VERSION 5.8 ;
BUSBITCHARS "[]" ;
DIVIDERCHAR "/" ;
CLEARANCEMEASURE EUCLIDEAN ;

SITE coresite
    SIZE 0.0450 BY 0.1440 ;
    CLASS CORE ;
    SYMMETRY Y ;
END coresite

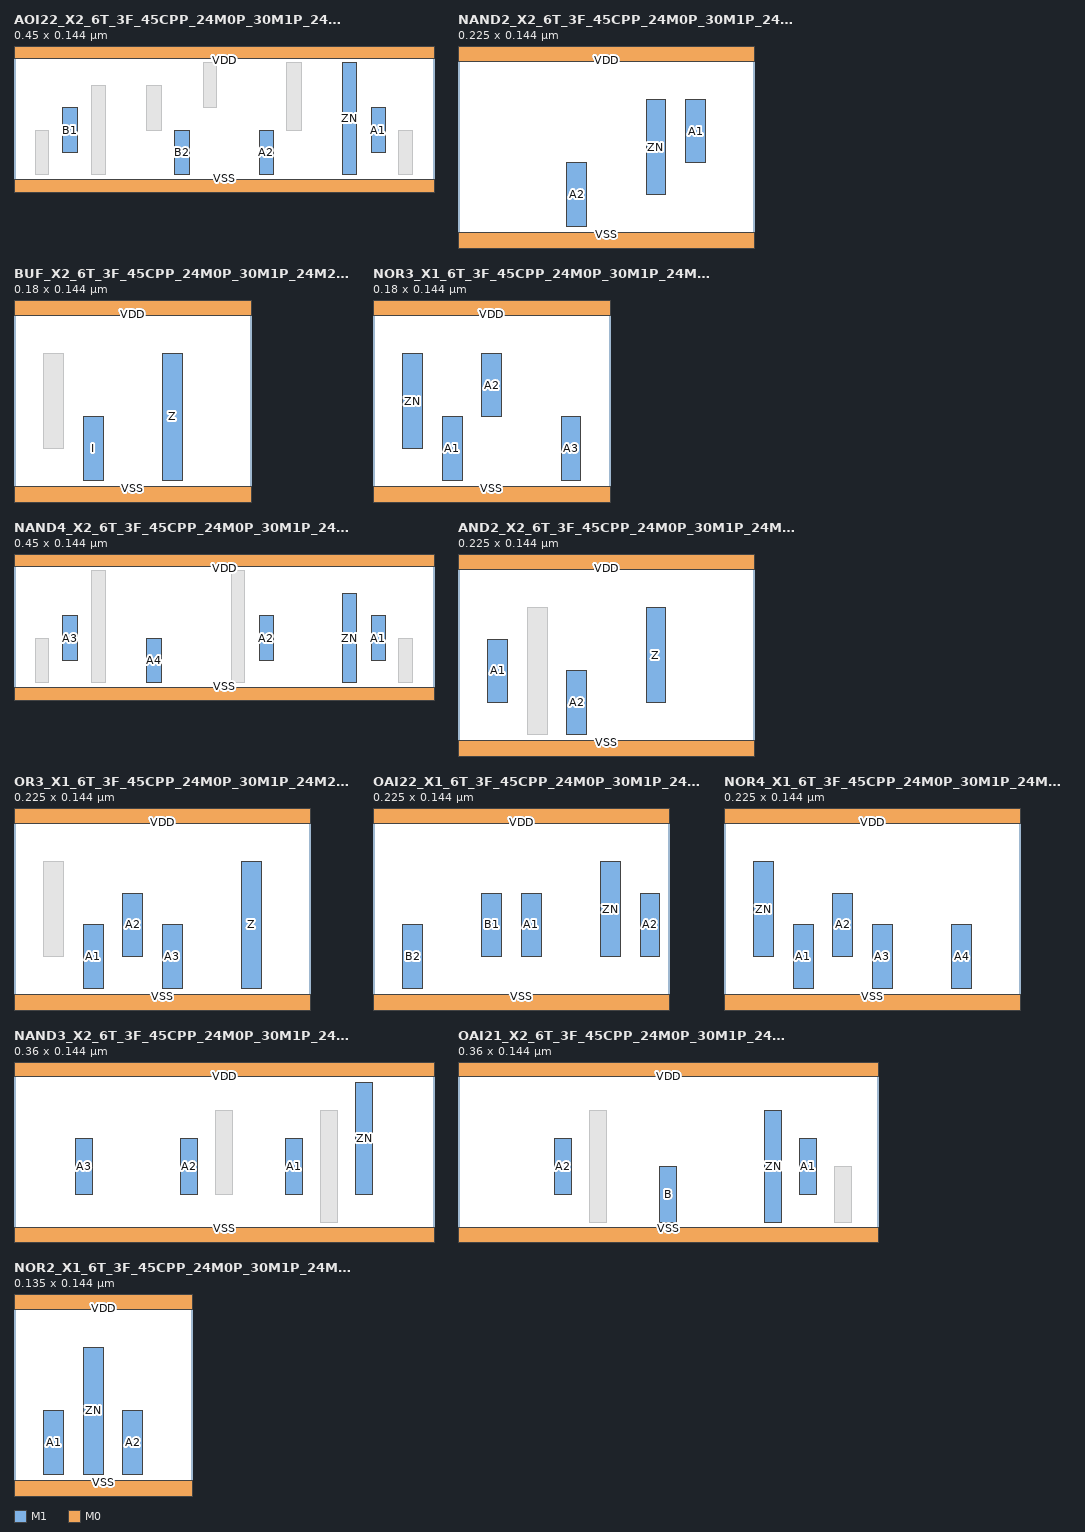
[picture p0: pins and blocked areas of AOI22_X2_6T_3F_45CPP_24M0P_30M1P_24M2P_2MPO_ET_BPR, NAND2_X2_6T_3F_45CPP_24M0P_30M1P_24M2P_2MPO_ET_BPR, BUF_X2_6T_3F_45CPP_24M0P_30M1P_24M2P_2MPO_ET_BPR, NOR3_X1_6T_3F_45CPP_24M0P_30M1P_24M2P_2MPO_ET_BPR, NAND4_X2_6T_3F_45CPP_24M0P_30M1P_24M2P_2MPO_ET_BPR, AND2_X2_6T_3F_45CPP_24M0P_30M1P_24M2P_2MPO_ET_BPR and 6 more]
MACRO AOI22_X2_6T_3F_45CPP_24M0P_30M1P_24M2P_2MPO_ET_BPR
  CLASS CORE ;
  ORIGIN 0 0 ;
  FOREIGN AOI22_X2_6T_3F_45CPP_24M0P_30M1P_24M2P_2MPO_ET_BPR 0 0 ;
  SIZE 0.4500 BY 0.1440 ;
  SYMMETRY X Y ;
  SITE coresite ;
  PIN A1
    DIRECTION INPUT ;
    USE SIGNAL ;
    PORT
      LAYER M1 ;
        RECT 0.3825 0.0840 0.3975 0.0360 ;
    END
  END A1
  PIN A2
    DIRECTION INPUT ;
    USE SIGNAL ;
    PORT
      LAYER M1 ;
        RECT 0.2625 0.0600 0.2775 0.0120 ;
    END
  END A2
  PIN ZN
    DIRECTION OUTPUT ;
    USE SIGNAL ;
    PORT
      LAYER M1 ;
        RECT 0.3525 0.1320 0.3675 0.0120 ;
    END
  END ZN
  PIN B1
    DIRECTION INPUT ;
    USE SIGNAL ;
    PORT
      LAYER M1 ;
        RECT 0.0525 0.0840 0.0675 0.0360 ;
    END
  END B1
  PIN B2
    DIRECTION INPUT ;
    USE SIGNAL ;
    PORT
      LAYER M1 ;
        RECT 0.1725 0.0600 0.1875 0.0120 ;
    END
  END B2
  PIN VDD
    DIRECTION INOUT ;
    USE POWER ;
    SHAPE ABUTMENT ;
    PORT
      LAYER M0 ;
        RECT 0.0000 0.1370 0.4500 0.1510 ;
    END
  END VDD
  PIN VSS
    DIRECTION INOUT ;
    USE GROUND ;
    SHAPE ABUTMENT ;
    PORT
      LAYER M0 ;
        RECT 0.0000 -0.0070 0.4500 0.0070 ;
    END
  END VSS
  OBS
      LAYER M1 ;
        RECT 0.0225 0.0600 0.0375 0.0120 ;
        RECT 0.2025 0.1320 0.2175 0.0840 ;
        RECT 0.4125 0.0600 0.4275 0.0120 ;
        RECT 0.1425 0.1080 0.1575 0.0600 ;
        RECT 0.0825 0.1080 0.0975 0.0120 ;
        RECT 0.2925 0.1320 0.3075 0.0600 ;
  END
END AOI22_X2_6T_3F_45CPP_24M0P_30M1P_24M2P_2MPO_ET_BPR

MACRO NAND2_X2_6T_3F_45CPP_24M0P_30M1P_24M2P_2MPO_ET_BPR
  CLASS CORE ;
  ORIGIN 0 0 ;
  FOREIGN NAND2_X2_6T_3F_45CPP_24M0P_30M1P_24M2P_2MPO_ET_BPR 0 0 ;
  SIZE 0.2250 BY 0.1440 ;
  SYMMETRY X Y ;
  SITE coresite ;
  PIN A2
    DIRECTION INPUT ;
    USE SIGNAL ;
    PORT
      LAYER M1 ;
        RECT 0.0825 0.0600 0.0975 0.0120 ;
    END
  END A2
  PIN A1
    DIRECTION INPUT ;
    USE SIGNAL ;
    PORT
      LAYER M1 ;
        RECT 0.1725 0.1080 0.1875 0.0600 ;
    END
  END A1
  PIN ZN
    DIRECTION OUTPUT ;
    USE SIGNAL ;
    PORT
      LAYER M1 ;
        RECT 0.1425 0.1080 0.1575 0.0360 ;
    END
  END ZN
  PIN VDD
    DIRECTION INOUT ;
    USE POWER ;
    SHAPE ABUTMENT ;
    PORT
      LAYER M0 ;
        RECT 0.0000 0.1370 0.2250 0.1510 ;
    END
  END VDD
  PIN VSS
    DIRECTION INOUT ;
    USE GROUND ;
    SHAPE ABUTMENT ;
    PORT
      LAYER M0 ;
        RECT 0.0000 -0.0070 0.2250 0.0070 ;
    END
  END VSS
END NAND2_X2_6T_3F_45CPP_24M0P_30M1P_24M2P_2MPO_ET_BPR

MACRO BUF_X2_6T_3F_45CPP_24M0P_30M1P_24M2P_2MPO_ET_BPR
  CLASS CORE ;
  ORIGIN 0 0 ;
  FOREIGN BUF_X2_6T_3F_45CPP_24M0P_30M1P_24M2P_2MPO_ET_BPR 0 0 ;
  SIZE 0.1800 BY 0.1440 ;
  SYMMETRY X Y ;
  SITE coresite ;
  PIN Z
    DIRECTION OUTPUT ;
    USE SIGNAL ;
    PORT
      LAYER M1 ;
        RECT 0.1125 0.1080 0.1275 0.0120 ;
    END
  END Z
  PIN I
    DIRECTION INPUT ;
    USE SIGNAL ;
    PORT
      LAYER M1 ;
        RECT 0.0525 0.0600 0.0675 0.0120 ;
    END
  END I
  PIN VDD
    DIRECTION INOUT ;
    USE POWER ;
    SHAPE ABUTMENT ;
    PORT
      LAYER M0 ;
        RECT 0.0000 0.1370 0.1800 0.1510 ;
    END
  END VDD
  PIN VSS
    DIRECTION INOUT ;
    USE GROUND ;
    SHAPE ABUTMENT ;
    PORT
      LAYER M0 ;
        RECT 0.0000 -0.0070 0.1800 0.0070 ;
    END
  END VSS
  OBS
      LAYER M1 ;
        RECT 0.0225 0.1080 0.0375 0.0360 ;
  END
END BUF_X2_6T_3F_45CPP_24M0P_30M1P_24M2P_2MPO_ET_BPR

MACRO NOR3_X1_6T_3F_45CPP_24M0P_30M1P_24M2P_2MPO_ET_BPR
  CLASS CORE ;
  ORIGIN 0 0 ;
  FOREIGN NOR3_X1_6T_3F_45CPP_24M0P_30M1P_24M2P_2MPO_ET_BPR 0 0 ;
  SIZE 0.1800 BY 0.1440 ;
  SYMMETRY X Y ;
  SITE coresite ;
  PIN A3
    DIRECTION INPUT ;
    USE SIGNAL ;
    PORT
      LAYER M1 ;
        RECT 0.1425 0.0600 0.1575 0.0120 ;
    END
  END A3
  PIN A2
    DIRECTION INPUT ;
    USE SIGNAL ;
    PORT
      LAYER M1 ;
        RECT 0.0825 0.1080 0.0975 0.0600 ;
    END
  END A2
  PIN A1
    DIRECTION INPUT ;
    USE SIGNAL ;
    PORT
      LAYER M1 ;
        RECT 0.0525 0.0600 0.0675 0.0120 ;
    END
  END A1
  PIN ZN
    DIRECTION OUTPUT ;
    USE SIGNAL ;
    PORT
      LAYER M1 ;
        RECT 0.0225 0.1080 0.0375 0.0360 ;
    END
  END ZN
  PIN VDD
    DIRECTION INOUT ;
    USE POWER ;
    SHAPE ABUTMENT ;
    PORT
      LAYER M0 ;
        RECT 0.0000 0.1370 0.1800 0.1510 ;
    END
  END VDD
  PIN VSS
    DIRECTION INOUT ;
    USE GROUND ;
    SHAPE ABUTMENT ;
    PORT
      LAYER M0 ;
        RECT 0.0000 -0.0070 0.1800 0.0070 ;
    END
  END VSS
END NOR3_X1_6T_3F_45CPP_24M0P_30M1P_24M2P_2MPO_ET_BPR

MACRO NAND4_X2_6T_3F_45CPP_24M0P_30M1P_24M2P_2MPO_ET_BPR
  CLASS CORE ;
  ORIGIN 0 0 ;
  FOREIGN NAND4_X2_6T_3F_45CPP_24M0P_30M1P_24M2P_2MPO_ET_BPR 0 0 ;
  SIZE 0.4500 BY 0.1440 ;
  SYMMETRY X Y ;
  SITE coresite ;
  PIN ZN
    DIRECTION OUTPUT ;
    USE SIGNAL ;
    PORT
      LAYER M1 ;
        RECT 0.3525 0.1080 0.3675 0.0120 ;
    END
  END ZN
  PIN A1
    DIRECTION INPUT ;
    USE SIGNAL ;
    PORT
      LAYER M1 ;
        RECT 0.3825 0.0840 0.3975 0.0360 ;
    END
  END A1
  PIN A2
    DIRECTION INPUT ;
    USE SIGNAL ;
    PORT
      LAYER M1 ;
        RECT 0.2625 0.0840 0.2775 0.0360 ;
    END
  END A2
  PIN A3
    DIRECTION INPUT ;
    USE SIGNAL ;
    PORT
      LAYER M1 ;
        RECT 0.0525 0.0840 0.0675 0.0360 ;
    END
  END A3
  PIN A4
    DIRECTION INPUT ;
    USE SIGNAL ;
    PORT
      LAYER M1 ;
        RECT 0.1425 0.0600 0.1575 0.0120 ;
    END
  END A4
  PIN VDD
    DIRECTION INOUT ;
    USE POWER ;
    SHAPE ABUTMENT ;
    PORT
      LAYER M0 ;
        RECT 0.0000 0.1370 0.4500 0.1510 ;
    END
  END VDD
  PIN VSS
    DIRECTION INOUT ;
    USE GROUND ;
    SHAPE ABUTMENT ;
    PORT
      LAYER M0 ;
        RECT 0.0000 -0.0070 0.4500 0.0070 ;
    END
  END VSS
  OBS
      LAYER M1 ;
        RECT 0.0825 0.1320 0.0975 0.0120 ;
        RECT 0.2325 0.1320 0.2475 0.0120 ;
        RECT 0.0225 0.0600 0.0375 0.0120 ;
        RECT 0.4125 0.0600 0.4275 0.0120 ;
  END
END NAND4_X2_6T_3F_45CPP_24M0P_30M1P_24M2P_2MPO_ET_BPR

MACRO AND2_X2_6T_3F_45CPP_24M0P_30M1P_24M2P_2MPO_ET_BPR
  CLASS CORE ;
  ORIGIN 0 0 ;
  FOREIGN AND2_X2_6T_3F_45CPP_24M0P_30M1P_24M2P_2MPO_ET_BPR 0 0 ;
  SIZE 0.2250 BY 0.1440 ;
  SYMMETRY X Y ;
  SITE coresite ;
  PIN Z
    DIRECTION OUTPUT ;
    USE SIGNAL ;
    PORT
      LAYER M1 ;
        RECT 0.1425 0.1080 0.1575 0.0360 ;
    END
  END Z
  PIN A1
    DIRECTION INPUT ;
    USE SIGNAL ;
    PORT
      LAYER M1 ;
        RECT 0.0225 0.0840 0.0375 0.0360 ;
    END
  END A1
  PIN A2
    DIRECTION INPUT ;
    USE SIGNAL ;
    PORT
      LAYER M1 ;
        RECT 0.0825 0.0600 0.0975 0.0120 ;
    END
  END A2
  PIN VDD
    DIRECTION INOUT ;
    USE POWER ;
    SHAPE ABUTMENT ;
    PORT
      LAYER M0 ;
        RECT 0.0000 0.1370 0.2250 0.1510 ;
    END
  END VDD
  PIN VSS
    DIRECTION INOUT ;
    USE GROUND ;
    SHAPE ABUTMENT ;
    PORT
      LAYER M0 ;
        RECT 0.0000 -0.0070 0.2250 0.0070 ;
    END
  END VSS
  OBS
      LAYER M1 ;
        RECT 0.0525 0.1080 0.0675 0.0120 ;
  END
END AND2_X2_6T_3F_45CPP_24M0P_30M1P_24M2P_2MPO_ET_BPR

MACRO OR3_X1_6T_3F_45CPP_24M0P_30M1P_24M2P_2MPO_ET_BPR
  CLASS CORE ;
  ORIGIN 0 0 ;
  FOREIGN OR3_X1_6T_3F_45CPP_24M0P_30M1P_24M2P_2MPO_ET_BPR 0 0 ;
  SIZE 0.2250 BY 0.1440 ;
  SYMMETRY X Y ;
  SITE coresite ;
  PIN Z
    DIRECTION OUTPUT ;
    USE SIGNAL ;
    PORT
      LAYER M1 ;
        RECT 0.1725 0.1080 0.1875 0.0120 ;
    END
  END Z
  PIN A1
    DIRECTION INPUT ;
    USE SIGNAL ;
    PORT
      LAYER M1 ;
        RECT 0.0525 0.0600 0.0675 0.0120 ;
    END
  END A1
  PIN A2
    DIRECTION INPUT ;
    USE SIGNAL ;
    PORT
      LAYER M1 ;
        RECT 0.0825 0.0840 0.0975 0.0360 ;
    END
  END A2
  PIN A3
    DIRECTION INPUT ;
    USE SIGNAL ;
    PORT
      LAYER M1 ;
        RECT 0.1125 0.0600 0.1275 0.0120 ;
    END
  END A3
  PIN VDD
    DIRECTION INOUT ;
    USE POWER ;
    SHAPE ABUTMENT ;
    PORT
      LAYER M0 ;
        RECT 0.0000 0.1370 0.2250 0.1510 ;
    END
  END VDD
  PIN VSS
    DIRECTION INOUT ;
    USE GROUND ;
    SHAPE ABUTMENT ;
    PORT
      LAYER M0 ;
        RECT 0.0000 -0.0070 0.2250 0.0070 ;
    END
  END VSS
  OBS
      LAYER M1 ;
        RECT 0.0225 0.1080 0.0375 0.0360 ;
  END
END OR3_X1_6T_3F_45CPP_24M0P_30M1P_24M2P_2MPO_ET_BPR

MACRO OAI22_X1_6T_3F_45CPP_24M0P_30M1P_24M2P_2MPO_ET_BPR
  CLASS CORE ;
  ORIGIN 0 0 ;
  FOREIGN OAI22_X1_6T_3F_45CPP_24M0P_30M1P_24M2P_2MPO_ET_BPR 0 0 ;
  SIZE 0.2250 BY 0.1440 ;
  SYMMETRY X Y ;
  SITE coresite ;
  PIN A2
    DIRECTION INPUT ;
    USE SIGNAL ;
    PORT
      LAYER M1 ;
        RECT 0.2025 0.0840 0.2175 0.0360 ;
    END
  END A2
  PIN ZN
    DIRECTION OUTPUT ;
    USE SIGNAL ;
    PORT
      LAYER M1 ;
        RECT 0.1725 0.1080 0.1875 0.0360 ;
    END
  END ZN
  PIN A1
    DIRECTION INPUT ;
    USE SIGNAL ;
    PORT
      LAYER M1 ;
        RECT 0.1125 0.0840 0.1275 0.0360 ;
    END
  END A1
  PIN B1
    DIRECTION INPUT ;
    USE SIGNAL ;
    PORT
      LAYER M1 ;
        RECT 0.0825 0.0840 0.0975 0.0360 ;
    END
  END B1
  PIN B2
    DIRECTION INPUT ;
    USE SIGNAL ;
    PORT
      LAYER M1 ;
        RECT 0.0225 0.0600 0.0375 0.0120 ;
    END
  END B2
  PIN VDD
    DIRECTION INOUT ;
    USE POWER ;
    SHAPE ABUTMENT ;
    PORT
      LAYER M0 ;
        RECT 0.0000 0.1370 0.2250 0.1510 ;
    END
  END VDD
  PIN VSS
    DIRECTION INOUT ;
    USE GROUND ;
    SHAPE ABUTMENT ;
    PORT
      LAYER M0 ;
        RECT 0.0000 -0.0070 0.2250 0.0070 ;
    END
  END VSS
END OAI22_X1_6T_3F_45CPP_24M0P_30M1P_24M2P_2MPO_ET_BPR

MACRO NOR4_X1_6T_3F_45CPP_24M0P_30M1P_24M2P_2MPO_ET_BPR
  CLASS CORE ;
  ORIGIN 0 0 ;
  FOREIGN NOR4_X1_6T_3F_45CPP_24M0P_30M1P_24M2P_2MPO_ET_BPR 0 0 ;
  SIZE 0.2250 BY 0.1440 ;
  SYMMETRY X Y ;
  SITE coresite ;
  PIN A4
    DIRECTION INPUT ;
    USE SIGNAL ;
    PORT
      LAYER M1 ;
        RECT 0.1725 0.0600 0.1875 0.0120 ;
    END
  END A4
  PIN A3
    DIRECTION INPUT ;
    USE SIGNAL ;
    PORT
      LAYER M1 ;
        RECT 0.1125 0.0600 0.1275 0.0120 ;
    END
  END A3
  PIN A2
    DIRECTION INPUT ;
    USE SIGNAL ;
    PORT
      LAYER M1 ;
        RECT 0.0825 0.0840 0.0975 0.0360 ;
    END
  END A2
  PIN A1
    DIRECTION INPUT ;
    USE SIGNAL ;
    PORT
      LAYER M1 ;
        RECT 0.0525 0.0600 0.0675 0.0120 ;
    END
  END A1
  PIN ZN
    DIRECTION OUTPUT ;
    USE SIGNAL ;
    PORT
      LAYER M1 ;
        RECT 0.0225 0.1080 0.0375 0.0360 ;
    END
  END ZN
  PIN VDD
    DIRECTION INOUT ;
    USE POWER ;
    SHAPE ABUTMENT ;
    PORT
      LAYER M0 ;
        RECT 0.0000 0.1370 0.2250 0.1510 ;
    END
  END VDD
  PIN VSS
    DIRECTION INOUT ;
    USE GROUND ;
    SHAPE ABUTMENT ;
    PORT
      LAYER M0 ;
        RECT 0.0000 -0.0070 0.2250 0.0070 ;
    END
  END VSS
END NOR4_X1_6T_3F_45CPP_24M0P_30M1P_24M2P_2MPO_ET_BPR

MACRO NAND3_X2_6T_3F_45CPP_24M0P_30M1P_24M2P_2MPO_ET_BPR
  CLASS CORE ;
  ORIGIN 0 0 ;
  FOREIGN NAND3_X2_6T_3F_45CPP_24M0P_30M1P_24M2P_2MPO_ET_BPR 0 0 ;
  SIZE 0.3600 BY 0.1440 ;
  SYMMETRY X Y ;
  SITE coresite ;
  PIN A1
    DIRECTION INPUT ;
    USE SIGNAL ;
    PORT
      LAYER M1 ;
        RECT 0.2325 0.0840 0.2475 0.0360 ;
    END
  END A1
  PIN ZN
    DIRECTION OUTPUT ;
    USE SIGNAL ;
    PORT
      LAYER M1 ;
        RECT 0.2925 0.1320 0.3075 0.0360 ;
    END
  END ZN
  PIN A2
    DIRECTION INPUT ;
    USE SIGNAL ;
    PORT
      LAYER M1 ;
        RECT 0.1425 0.0840 0.1575 0.0360 ;
    END
  END A2
  PIN A3
    DIRECTION INPUT ;
    USE SIGNAL ;
    PORT
      LAYER M1 ;
        RECT 0.0525 0.0840 0.0675 0.0360 ;
    END
  END A3
  PIN VDD
    DIRECTION INOUT ;
    USE POWER ;
    SHAPE ABUTMENT ;
    PORT
      LAYER M0 ;
        RECT 0.0000 0.1370 0.3600 0.1510 ;
    END
  END VDD
  PIN VSS
    DIRECTION INOUT ;
    USE GROUND ;
    SHAPE ABUTMENT ;
    PORT
      LAYER M0 ;
        RECT 0.0000 -0.0070 0.3600 0.0070 ;
    END
  END VSS
  OBS
      LAYER M1 ;
        RECT 0.2625 0.1080 0.2775 0.0120 ;
        RECT 0.1725 0.1080 0.1875 0.0360 ;
  END
END NAND3_X2_6T_3F_45CPP_24M0P_30M1P_24M2P_2MPO_ET_BPR

MACRO OAI21_X2_6T_3F_45CPP_24M0P_30M1P_24M2P_2MPO_ET_BPR
  CLASS CORE ;
  ORIGIN 0 0 ;
  FOREIGN OAI21_X2_6T_3F_45CPP_24M0P_30M1P_24M2P_2MPO_ET_BPR 0 0 ;
  SIZE 0.3600 BY 0.1440 ;
  SYMMETRY X Y ;
  SITE coresite ;
  PIN A2
    DIRECTION INPUT ;
    USE SIGNAL ;
    PORT
      LAYER M1 ;
        RECT 0.0825 0.0840 0.0975 0.0360 ;
    END
  END A2
  PIN A1
    DIRECTION INPUT ;
    USE SIGNAL ;
    PORT
      LAYER M1 ;
        RECT 0.2925 0.0840 0.3075 0.0360 ;
    END
  END A1
  PIN ZN
    DIRECTION OUTPUT ;
    USE SIGNAL ;
    PORT
      LAYER M1 ;
        RECT 0.2625 0.1080 0.2775 0.0120 ;
    END
  END ZN
  PIN B
    DIRECTION INPUT ;
    USE SIGNAL ;
    PORT
      LAYER M1 ;
        RECT 0.1725 0.0600 0.1875 0.0120 ;
    END
  END B
  PIN VDD
    DIRECTION INOUT ;
    USE POWER ;
    SHAPE ABUTMENT ;
    PORT
      LAYER M0 ;
        RECT 0.0000 0.1370 0.3600 0.1510 ;
    END
  END VDD
  PIN VSS
    DIRECTION INOUT ;
    USE GROUND ;
    SHAPE ABUTMENT ;
    PORT
      LAYER M0 ;
        RECT 0.0000 -0.0070 0.3600 0.0070 ;
    END
  END VSS
  OBS
      LAYER M1 ;
        RECT 0.3225 0.0600 0.3375 0.0120 ;
        RECT 0.1125 0.1080 0.1275 0.0120 ;
  END
END OAI21_X2_6T_3F_45CPP_24M0P_30M1P_24M2P_2MPO_ET_BPR

MACRO NOR2_X1_6T_3F_45CPP_24M0P_30M1P_24M2P_2MPO_ET_BPR
  CLASS CORE ;
  ORIGIN 0 0 ;
  FOREIGN NOR2_X1_6T_3F_45CPP_24M0P_30M1P_24M2P_2MPO_ET_BPR 0 0 ;
  SIZE 0.1350 BY 0.1440 ;
  SYMMETRY X Y ;
  SITE coresite ;
  PIN A2
    DIRECTION INPUT ;
    USE SIGNAL ;
    PORT
      LAYER M1 ;
        RECT 0.0825 0.0600 0.0975 0.0120 ;
    END
  END A2
  PIN A1
    DIRECTION INPUT ;
    USE SIGNAL ;
    PORT
      LAYER M1 ;
        RECT 0.0225 0.0600 0.0375 0.0120 ;
    END
  END A1
  PIN ZN
    DIRECTION OUTPUT ;
    USE SIGNAL ;
    PORT
      LAYER M1 ;
        RECT 0.0525 0.1080 0.0675 0.0120 ;
    END
  END ZN
  PIN VDD
    DIRECTION INOUT ;
    USE POWER ;
    SHAPE ABUTMENT ;
    PORT
      LAYER M0 ;
        RECT 0.0000 0.1370 0.1350 0.1510 ;
    END
  END VDD
  PIN VSS
    DIRECTION INOUT ;
    USE GROUND ;
    SHAPE ABUTMENT ;
    PORT
      LAYER M0 ;
        RECT 0.0000 -0.0070 0.1350 0.0070 ;
    END
  END VSS
END NOR2_X1_6T_3F_45CPP_24M0P_30M1P_24M2P_2MPO_ET_BPR

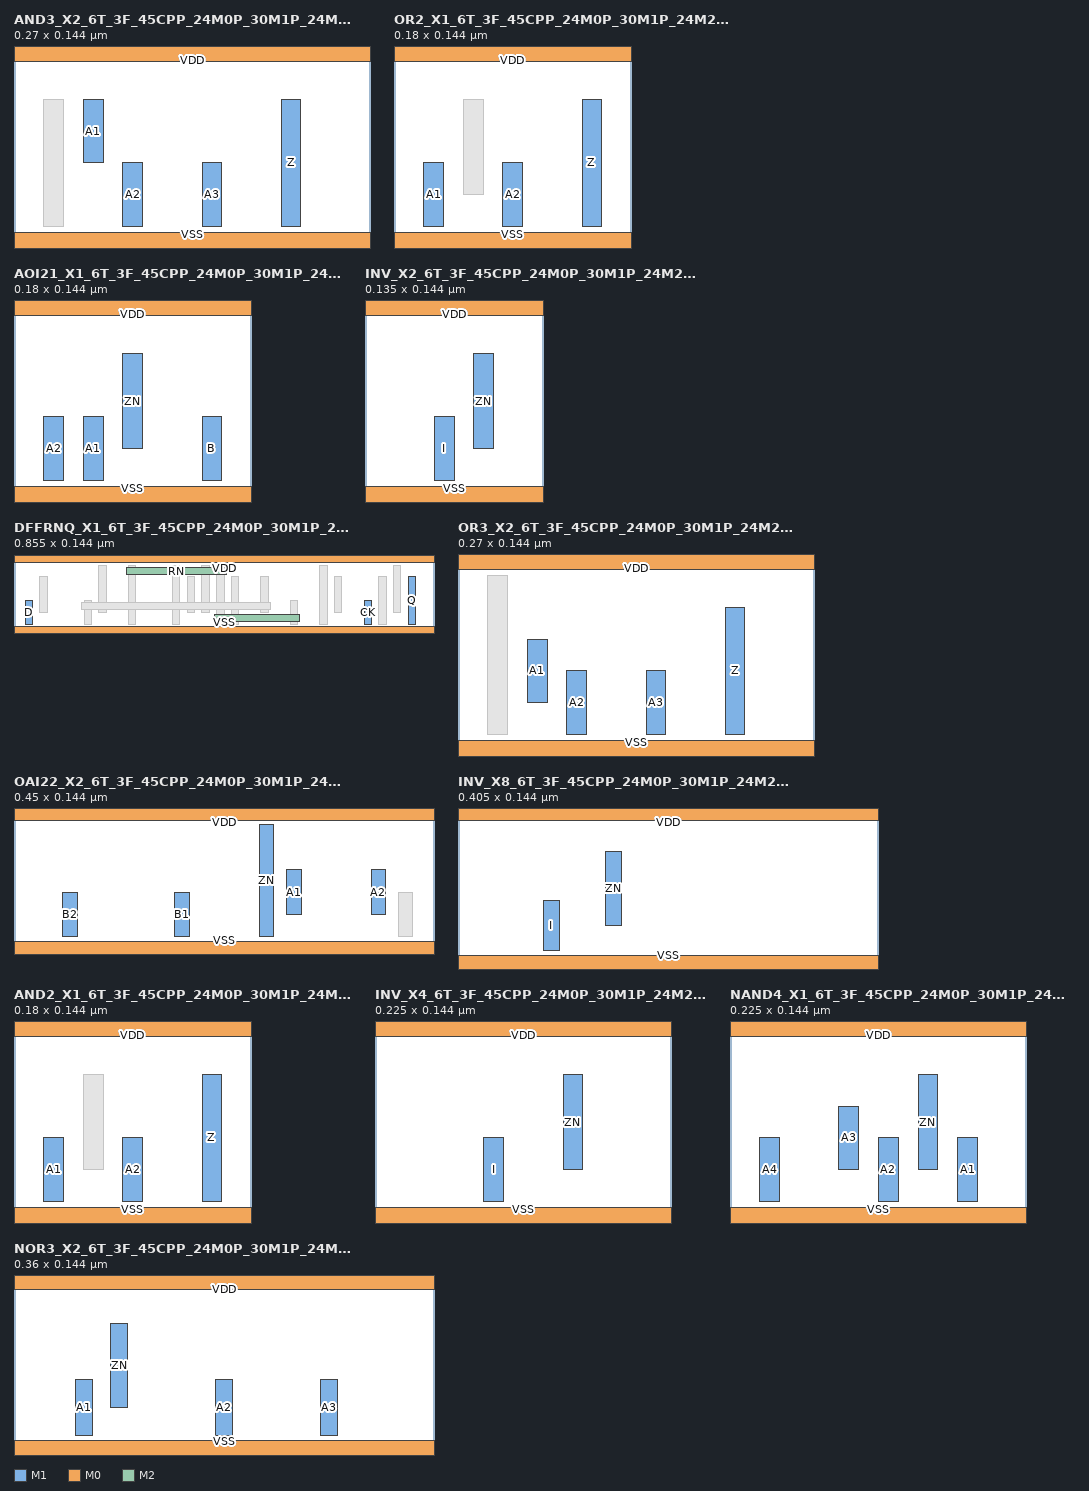
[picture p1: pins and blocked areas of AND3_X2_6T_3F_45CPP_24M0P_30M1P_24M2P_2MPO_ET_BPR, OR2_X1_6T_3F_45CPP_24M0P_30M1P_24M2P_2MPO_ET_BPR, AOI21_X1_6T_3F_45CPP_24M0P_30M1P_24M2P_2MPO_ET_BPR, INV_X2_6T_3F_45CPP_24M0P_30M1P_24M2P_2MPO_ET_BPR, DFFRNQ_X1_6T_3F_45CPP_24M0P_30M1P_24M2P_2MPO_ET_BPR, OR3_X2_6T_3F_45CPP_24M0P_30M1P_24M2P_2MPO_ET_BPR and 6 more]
MACRO AND3_X2_6T_3F_45CPP_24M0P_30M1P_24M2P_2MPO_ET_BPR
  CLASS CORE ;
  ORIGIN 0 0 ;
  FOREIGN AND3_X2_6T_3F_45CPP_24M0P_30M1P_24M2P_2MPO_ET_BPR 0 0 ;
  SIZE 0.2700 BY 0.1440 ;
  SYMMETRY X Y ;
  SITE coresite ;
  PIN Z
    DIRECTION OUTPUT ;
    USE SIGNAL ;
    PORT
      LAYER M1 ;
        RECT 0.2025 0.1080 0.2175 0.0120 ;
    END
  END Z
  PIN A3
    DIRECTION INPUT ;
    USE SIGNAL ;
    PORT
      LAYER M1 ;
        RECT 0.1425 0.0600 0.1575 0.0120 ;
    END
  END A3
  PIN A1
    DIRECTION INPUT ;
    USE SIGNAL ;
    PORT
      LAYER M1 ;
        RECT 0.0525 0.1080 0.0675 0.0600 ;
    END
  END A1
  PIN A2
    DIRECTION INPUT ;
    USE SIGNAL ;
    PORT
      LAYER M1 ;
        RECT 0.0825 0.0600 0.0975 0.0120 ;
    END
  END A2
  PIN VDD
    DIRECTION INOUT ;
    USE POWER ;
    SHAPE ABUTMENT ;
    PORT
      LAYER M0 ;
        RECT 0.0000 0.1370 0.2700 0.1510 ;
    END
  END VDD
  PIN VSS
    DIRECTION INOUT ;
    USE GROUND ;
    SHAPE ABUTMENT ;
    PORT
      LAYER M0 ;
        RECT 0.0000 -0.0070 0.2700 0.0070 ;
    END
  END VSS
  OBS
      LAYER M1 ;
        RECT 0.0225 0.1080 0.0375 0.0120 ;
  END
END AND3_X2_6T_3F_45CPP_24M0P_30M1P_24M2P_2MPO_ET_BPR

MACRO OR2_X1_6T_3F_45CPP_24M0P_30M1P_24M2P_2MPO_ET_BPR
  CLASS CORE ;
  ORIGIN 0 0 ;
  FOREIGN OR2_X1_6T_3F_45CPP_24M0P_30M1P_24M2P_2MPO_ET_BPR 0 0 ;
  SIZE 0.1800 BY 0.1440 ;
  SYMMETRY X Y ;
  SITE coresite ;
  PIN Z
    DIRECTION OUTPUT ;
    USE SIGNAL ;
    PORT
      LAYER M1 ;
        RECT 0.1425 0.1080 0.1575 0.0120 ;
    END
  END Z
  PIN A1
    DIRECTION INPUT ;
    USE SIGNAL ;
    PORT
      LAYER M1 ;
        RECT 0.0225 0.0600 0.0375 0.0120 ;
    END
  END A1
  PIN A2
    DIRECTION INPUT ;
    USE SIGNAL ;
    PORT
      LAYER M1 ;
        RECT 0.0825 0.0600 0.0975 0.0120 ;
    END
  END A2
  PIN VDD
    DIRECTION INOUT ;
    USE POWER ;
    SHAPE ABUTMENT ;
    PORT
      LAYER M0 ;
        RECT 0.0000 0.1370 0.1800 0.1510 ;
    END
  END VDD
  PIN VSS
    DIRECTION INOUT ;
    USE GROUND ;
    SHAPE ABUTMENT ;
    PORT
      LAYER M0 ;
        RECT 0.0000 -0.0070 0.1800 0.0070 ;
    END
  END VSS
  OBS
      LAYER M1 ;
        RECT 0.0525 0.1080 0.0675 0.0360 ;
  END
END OR2_X1_6T_3F_45CPP_24M0P_30M1P_24M2P_2MPO_ET_BPR

MACRO AOI21_X1_6T_3F_45CPP_24M0P_30M1P_24M2P_2MPO_ET_BPR
  CLASS CORE ;
  ORIGIN 0 0 ;
  FOREIGN AOI21_X1_6T_3F_45CPP_24M0P_30M1P_24M2P_2MPO_ET_BPR 0 0 ;
  SIZE 0.1800 BY 0.1440 ;
  SYMMETRY X Y ;
  SITE coresite ;
  PIN B
    DIRECTION INPUT ;
    USE SIGNAL ;
    PORT
      LAYER M1 ;
        RECT 0.1425 0.0600 0.1575 0.0120 ;
    END
  END B
  PIN ZN
    DIRECTION OUTPUT ;
    USE SIGNAL ;
    PORT
      LAYER M1 ;
        RECT 0.0825 0.1080 0.0975 0.0360 ;
    END
  END ZN
  PIN A1
    DIRECTION INPUT ;
    USE SIGNAL ;
    PORT
      LAYER M1 ;
        RECT 0.0525 0.0600 0.0675 0.0120 ;
    END
  END A1
  PIN A2
    DIRECTION INPUT ;
    USE SIGNAL ;
    PORT
      LAYER M1 ;
        RECT 0.0225 0.0600 0.0375 0.0120 ;
    END
  END A2
  PIN VDD
    DIRECTION INOUT ;
    USE POWER ;
    SHAPE ABUTMENT ;
    PORT
      LAYER M0 ;
        RECT 0.0000 0.1370 0.1800 0.1510 ;
    END
  END VDD
  PIN VSS
    DIRECTION INOUT ;
    USE GROUND ;
    SHAPE ABUTMENT ;
    PORT
      LAYER M0 ;
        RECT 0.0000 -0.0070 0.1800 0.0070 ;
    END
  END VSS
END AOI21_X1_6T_3F_45CPP_24M0P_30M1P_24M2P_2MPO_ET_BPR

MACRO INV_X2_6T_3F_45CPP_24M0P_30M1P_24M2P_2MPO_ET_BPR
  CLASS CORE ;
  ORIGIN 0 0 ;
  FOREIGN INV_X2_6T_3F_45CPP_24M0P_30M1P_24M2P_2MPO_ET_BPR 0 0 ;
  SIZE 0.1350 BY 0.1440 ;
  SYMMETRY X Y ;
  SITE coresite ;
  PIN ZN
    DIRECTION OUTPUT ;
    USE SIGNAL ;
    PORT
      LAYER M1 ;
        RECT 0.0825 0.1080 0.0975 0.0360 ;
    END
  END ZN
  PIN I
    DIRECTION INPUT ;
    USE SIGNAL ;
    PORT
      LAYER M1 ;
        RECT 0.0525 0.0600 0.0675 0.0120 ;
    END
  END I
  PIN VDD
    DIRECTION INOUT ;
    USE POWER ;
    SHAPE ABUTMENT ;
    PORT
      LAYER M0 ;
        RECT 0.0000 0.1370 0.1350 0.1510 ;
    END
  END VDD
  PIN VSS
    DIRECTION INOUT ;
    USE GROUND ;
    SHAPE ABUTMENT ;
    PORT
      LAYER M0 ;
        RECT 0.0000 -0.0070 0.1350 0.0070 ;
    END
  END VSS
END INV_X2_6T_3F_45CPP_24M0P_30M1P_24M2P_2MPO_ET_BPR

MACRO DFFRNQ_X1_6T_3F_45CPP_24M0P_30M1P_24M2P_2MPO_ET_BPR
  CLASS CORE ;
  ORIGIN 0 0 ;
  FOREIGN DFFRNQ_X1_6T_3F_45CPP_24M0P_30M1P_24M2P_2MPO_ET_BPR 0 0 ;
  SIZE 0.8550 BY 0.1440 ;
  SYMMETRY X Y ;
  SITE coresite ;
  PIN Q
    DIRECTION OUTPUT ;
    USE SIGNAL ;
    PORT
      LAYER M1 ;
        RECT 0.8025 0.1080 0.8175 0.0120 ;
    END
  END Q
  PIN RN
    DIRECTION INPUT ;
    USE SIGNAL ;
    PORT
      LAYER M2 ;
        RECT 0.4080 0.0170 0.5820 0.0310 ;
        RECT 0.2280 0.1130 0.4320 0.1270 ;
    END
  END RN
  PIN D
    DIRECTION INPUT ;
    USE SIGNAL ;
    PORT
      LAYER M1 ;
        RECT 0.0225 0.0600 0.0375 0.0120 ;
    END
  END D
  PIN CK
    DIRECTION INPUT ;
    USE SIGNAL ;
    PORT
      LAYER M1 ;
        RECT 0.7125 0.0600 0.7275 0.0120 ;
    END
  END CK
  PIN VDD
    DIRECTION INOUT ;
    USE POWER ;
    SHAPE ABUTMENT ;
    PORT
      LAYER M0 ;
        RECT 0.0000 0.1370 0.8550 0.1510 ;
    END
  END VDD
  PIN VSS
    DIRECTION INOUT ;
    USE GROUND ;
    SHAPE ABUTMENT ;
    PORT
      LAYER M0 ;
        RECT 0.0000 -0.0070 0.8550 0.0070 ;
    END
  END VSS
  OBS
      LAYER V1 ;
        RECT 0.5030 0.0410 0.5170 0.0550 ;
        RECT 0.3830 0.0410 0.3970 0.0550 ;
        RECT 0.1430 0.0410 0.1570 0.0550 ;
        RECT 0.5630 0.0170 0.5770 0.0310 ;
        RECT 0.4130 0.0170 0.4270 0.0310 ;
        RECT 0.4130 0.1130 0.4270 0.1270 ;
        RECT 0.2330 0.1130 0.2470 0.1270 ;
      LAYER M1 ;
        RECT 0.4425 0.1080 0.4575 0.0120 ;
        RECT 0.6225 0.1320 0.6375 0.0120 ;
        RECT 0.1725 0.1320 0.1875 0.0360 ;
        RECT 0.3825 0.1320 0.3975 0.0360 ;
        RECT 0.7425 0.1080 0.7575 0.0120 ;
        RECT 0.5025 0.1080 0.5175 0.0360 ;
        RECT 0.3525 0.1080 0.3675 0.0360 ;
        RECT 0.6525 0.1080 0.6675 0.0360 ;
        RECT 0.0525 0.1080 0.0675 0.0360 ;
        RECT 0.3225 0.1320 0.3375 0.0120 ;
        RECT 0.7725 0.1320 0.7875 0.0360 ;
        RECT 0.1425 0.0600 0.1575 0.0120 ;
        RECT 0.4125 0.1320 0.4275 0.0120 ;
        RECT 0.2325 0.1320 0.2475 0.0120 ;
        RECT 0.5625 0.0600 0.5775 0.0120 ;
      LAYER M2 ;
        RECT 0.1380 0.0410 0.5220 0.0550 ;
  END
END DFFRNQ_X1_6T_3F_45CPP_24M0P_30M1P_24M2P_2MPO_ET_BPR

MACRO OR3_X2_6T_3F_45CPP_24M0P_30M1P_24M2P_2MPO_ET_BPR
  CLASS CORE ;
  ORIGIN 0 0 ;
  FOREIGN OR3_X2_6T_3F_45CPP_24M0P_30M1P_24M2P_2MPO_ET_BPR 0 0 ;
  SIZE 0.2700 BY 0.1440 ;
  SYMMETRY X Y ;
  SITE coresite ;
  PIN Z
    DIRECTION OUTPUT ;
    USE SIGNAL ;
    PORT
      LAYER M1 ;
        RECT 0.2025 0.1080 0.2175 0.0120 ;
    END
  END Z
  PIN A3
    DIRECTION INPUT ;
    USE SIGNAL ;
    PORT
      LAYER M1 ;
        RECT 0.1425 0.0600 0.1575 0.0120 ;
    END
  END A3
  PIN A1
    DIRECTION INPUT ;
    USE SIGNAL ;
    PORT
      LAYER M1 ;
        RECT 0.0525 0.0840 0.0675 0.0360 ;
    END
  END A1
  PIN A2
    DIRECTION INPUT ;
    USE SIGNAL ;
    PORT
      LAYER M1 ;
        RECT 0.0825 0.0600 0.0975 0.0120 ;
    END
  END A2
  PIN VDD
    DIRECTION INOUT ;
    USE POWER ;
    SHAPE ABUTMENT ;
    PORT
      LAYER M0 ;
        RECT 0.0000 0.1370 0.2700 0.1510 ;
    END
  END VDD
  PIN VSS
    DIRECTION INOUT ;
    USE GROUND ;
    SHAPE ABUTMENT ;
    PORT
      LAYER M0 ;
        RECT 0.0000 -0.0070 0.2700 0.0070 ;
    END
  END VSS
  OBS
      LAYER M1 ;
        RECT 0.0225 0.1320 0.0375 0.0120 ;
  END
END OR3_X2_6T_3F_45CPP_24M0P_30M1P_24M2P_2MPO_ET_BPR

MACRO OAI22_X2_6T_3F_45CPP_24M0P_30M1P_24M2P_2MPO_ET_BPR
  CLASS CORE ;
  ORIGIN 0 0 ;
  FOREIGN OAI22_X2_6T_3F_45CPP_24M0P_30M1P_24M2P_2MPO_ET_BPR 0 0 ;
  SIZE 0.4500 BY 0.1440 ;
  SYMMETRY X Y ;
  SITE coresite ;
  PIN A1
    DIRECTION INPUT ;
    USE SIGNAL ;
    PORT
      LAYER M1 ;
        RECT 0.2925 0.0840 0.3075 0.0360 ;
    END
  END A1
  PIN ZN
    DIRECTION OUTPUT ;
    USE SIGNAL ;
    PORT
      LAYER M1 ;
        RECT 0.2625 0.1320 0.2775 0.0120 ;
    END
  END ZN
  PIN A2
    DIRECTION INPUT ;
    USE SIGNAL ;
    PORT
      LAYER M1 ;
        RECT 0.3825 0.0840 0.3975 0.0360 ;
    END
  END A2
  PIN B1
    DIRECTION INPUT ;
    USE SIGNAL ;
    PORT
      LAYER M1 ;
        RECT 0.1725 0.0600 0.1875 0.0120 ;
    END
  END B1
  PIN B2
    DIRECTION INPUT ;
    USE SIGNAL ;
    PORT
      LAYER M1 ;
        RECT 0.0525 0.0600 0.0675 0.0120 ;
    END
  END B2
  PIN VDD
    DIRECTION INOUT ;
    USE POWER ;
    SHAPE ABUTMENT ;
    PORT
      LAYER M0 ;
        RECT 0.0000 0.1370 0.4500 0.1510 ;
    END
  END VDD
  PIN VSS
    DIRECTION INOUT ;
    USE GROUND ;
    SHAPE ABUTMENT ;
    PORT
      LAYER M0 ;
        RECT 0.0000 -0.0070 0.4500 0.0070 ;
    END
  END VSS
  OBS
      LAYER M1 ;
        RECT 0.4125 0.0600 0.4275 0.0120 ;
  END
END OAI22_X2_6T_3F_45CPP_24M0P_30M1P_24M2P_2MPO_ET_BPR

MACRO INV_X8_6T_3F_45CPP_24M0P_30M1P_24M2P_2MPO_ET_BPR
  CLASS CORE ;
  ORIGIN 0 0 ;
  FOREIGN INV_X8_6T_3F_45CPP_24M0P_30M1P_24M2P_2MPO_ET_BPR 0 0 ;
  SIZE 0.4050 BY 0.1440 ;
  SYMMETRY X Y ;
  SITE coresite ;
  PIN ZN
    DIRECTION OUTPUT ;
    USE SIGNAL ;
    PORT
      LAYER M1 ;
        RECT 0.1425 0.1080 0.1575 0.0360 ;
    END
  END ZN
  PIN I
    DIRECTION INPUT ;
    USE SIGNAL ;
    PORT
      LAYER M1 ;
        RECT 0.0825 0.0600 0.0975 0.0120 ;
    END
  END I
  PIN VDD
    DIRECTION INOUT ;
    USE POWER ;
    SHAPE ABUTMENT ;
    PORT
      LAYER M0 ;
        RECT 0.0000 0.1370 0.4050 0.1510 ;
    END
  END VDD
  PIN VSS
    DIRECTION INOUT ;
    USE GROUND ;
    SHAPE ABUTMENT ;
    PORT
      LAYER M0 ;
        RECT 0.0000 -0.0070 0.4050 0.0070 ;
    END
  END VSS
END INV_X8_6T_3F_45CPP_24M0P_30M1P_24M2P_2MPO_ET_BPR

MACRO AND2_X1_6T_3F_45CPP_24M0P_30M1P_24M2P_2MPO_ET_BPR
  CLASS CORE ;
  ORIGIN 0 0 ;
  FOREIGN AND2_X1_6T_3F_45CPP_24M0P_30M1P_24M2P_2MPO_ET_BPR 0 0 ;
  SIZE 0.1800 BY 0.1440 ;
  SYMMETRY X Y ;
  SITE coresite ;
  PIN Z
    DIRECTION OUTPUT ;
    USE SIGNAL ;
    PORT
      LAYER M1 ;
        RECT 0.1425 0.1080 0.1575 0.0120 ;
    END
  END Z
  PIN A1
    DIRECTION INPUT ;
    USE SIGNAL ;
    PORT
      LAYER M1 ;
        RECT 0.0225 0.0600 0.0375 0.0120 ;
    END
  END A1
  PIN A2
    DIRECTION INPUT ;
    USE SIGNAL ;
    PORT
      LAYER M1 ;
        RECT 0.0825 0.0600 0.0975 0.0120 ;
    END
  END A2
  PIN VDD
    DIRECTION INOUT ;
    USE POWER ;
    SHAPE ABUTMENT ;
    PORT
      LAYER M0 ;
        RECT 0.0000 0.1370 0.1800 0.1510 ;
    END
  END VDD
  PIN VSS
    DIRECTION INOUT ;
    USE GROUND ;
    SHAPE ABUTMENT ;
    PORT
      LAYER M0 ;
        RECT 0.0000 -0.0070 0.1800 0.0070 ;
    END
  END VSS
  OBS
      LAYER M1 ;
        RECT 0.0525 0.1080 0.0675 0.0360 ;
  END
END AND2_X1_6T_3F_45CPP_24M0P_30M1P_24M2P_2MPO_ET_BPR

MACRO INV_X4_6T_3F_45CPP_24M0P_30M1P_24M2P_2MPO_ET_BPR
  CLASS CORE ;
  ORIGIN 0 0 ;
  FOREIGN INV_X4_6T_3F_45CPP_24M0P_30M1P_24M2P_2MPO_ET_BPR 0 0 ;
  SIZE 0.2250 BY 0.1440 ;
  SYMMETRY X Y ;
  SITE coresite ;
  PIN ZN
    DIRECTION OUTPUT ;
    USE SIGNAL ;
    PORT
      LAYER M1 ;
        RECT 0.1425 0.1080 0.1575 0.0360 ;
    END
  END ZN
  PIN I
    DIRECTION INPUT ;
    USE SIGNAL ;
    PORT
      LAYER M1 ;
        RECT 0.0825 0.0600 0.0975 0.0120 ;
    END
  END I
  PIN VDD
    DIRECTION INOUT ;
    USE POWER ;
    SHAPE ABUTMENT ;
    PORT
      LAYER M0 ;
        RECT 0.0000 0.1370 0.2250 0.1510 ;
    END
  END VDD
  PIN VSS
    DIRECTION INOUT ;
    USE GROUND ;
    SHAPE ABUTMENT ;
    PORT
      LAYER M0 ;
        RECT 0.0000 -0.0070 0.2250 0.0070 ;
    END
  END VSS
END INV_X4_6T_3F_45CPP_24M0P_30M1P_24M2P_2MPO_ET_BPR

MACRO NAND4_X1_6T_3F_45CPP_24M0P_30M1P_24M2P_2MPO_ET_BPR
  CLASS CORE ;
  ORIGIN 0 0 ;
  FOREIGN NAND4_X1_6T_3F_45CPP_24M0P_30M1P_24M2P_2MPO_ET_BPR 0 0 ;
  SIZE 0.2250 BY 0.1440 ;
  SYMMETRY X Y ;
  SITE coresite ;
  PIN ZN
    DIRECTION OUTPUT ;
    USE SIGNAL ;
    PORT
      LAYER M1 ;
        RECT 0.1425 0.1080 0.1575 0.0360 ;
    END
  END ZN
  PIN A1
    DIRECTION INPUT ;
    USE SIGNAL ;
    PORT
      LAYER M1 ;
        RECT 0.1725 0.0600 0.1875 0.0120 ;
    END
  END A1
  PIN A2
    DIRECTION INPUT ;
    USE SIGNAL ;
    PORT
      LAYER M1 ;
        RECT 0.1125 0.0600 0.1275 0.0120 ;
    END
  END A2
  PIN A3
    DIRECTION INPUT ;
    USE SIGNAL ;
    PORT
      LAYER M1 ;
        RECT 0.0825 0.0840 0.0975 0.0360 ;
    END
  END A3
  PIN A4
    DIRECTION INPUT ;
    USE SIGNAL ;
    PORT
      LAYER M1 ;
        RECT 0.0225 0.0600 0.0375 0.0120 ;
    END
  END A4
  PIN VDD
    DIRECTION INOUT ;
    USE POWER ;
    SHAPE ABUTMENT ;
    PORT
      LAYER M0 ;
        RECT 0.0000 0.1370 0.2250 0.1510 ;
    END
  END VDD
  PIN VSS
    DIRECTION INOUT ;
    USE GROUND ;
    SHAPE ABUTMENT ;
    PORT
      LAYER M0 ;
        RECT 0.0000 -0.0070 0.2250 0.0070 ;
    END
  END VSS
END NAND4_X1_6T_3F_45CPP_24M0P_30M1P_24M2P_2MPO_ET_BPR

MACRO NOR3_X2_6T_3F_45CPP_24M0P_30M1P_24M2P_2MPO_ET_BPR
  CLASS CORE ;
  ORIGIN 0 0 ;
  FOREIGN NOR3_X2_6T_3F_45CPP_24M0P_30M1P_24M2P_2MPO_ET_BPR 0 0 ;
  SIZE 0.3600 BY 0.1440 ;
  SYMMETRY X Y ;
  SITE coresite ;
  PIN A3
    DIRECTION INPUT ;
    USE SIGNAL ;
    PORT
      LAYER M1 ;
        RECT 0.2625 0.0600 0.2775 0.0120 ;
    END
  END A3
  PIN A2
    DIRECTION INPUT ;
    USE SIGNAL ;
    PORT
      LAYER M1 ;
        RECT 0.1725 0.0600 0.1875 0.0120 ;
    END
  END A2
  PIN A1
    DIRECTION INPUT ;
    USE SIGNAL ;
    PORT
      LAYER M1 ;
        RECT 0.0525 0.0600 0.0675 0.0120 ;
    END
  END A1
  PIN ZN
    DIRECTION OUTPUT ;
    USE SIGNAL ;
    PORT
      LAYER M1 ;
        RECT 0.0825 0.1080 0.0975 0.0360 ;
    END
  END ZN
  PIN VDD
    DIRECTION INOUT ;
    USE POWER ;
    SHAPE ABUTMENT ;
    PORT
      LAYER M0 ;
        RECT 0.0000 0.1370 0.3600 0.1510 ;
    END
  END VDD
  PIN VSS
    DIRECTION INOUT ;
    USE GROUND ;
    SHAPE ABUTMENT ;
    PORT
      LAYER M0 ;
        RECT 0.0000 -0.0070 0.3600 0.0070 ;
    END
  END VSS
END NOR3_X2_6T_3F_45CPP_24M0P_30M1P_24M2P_2MPO_ET_BPR

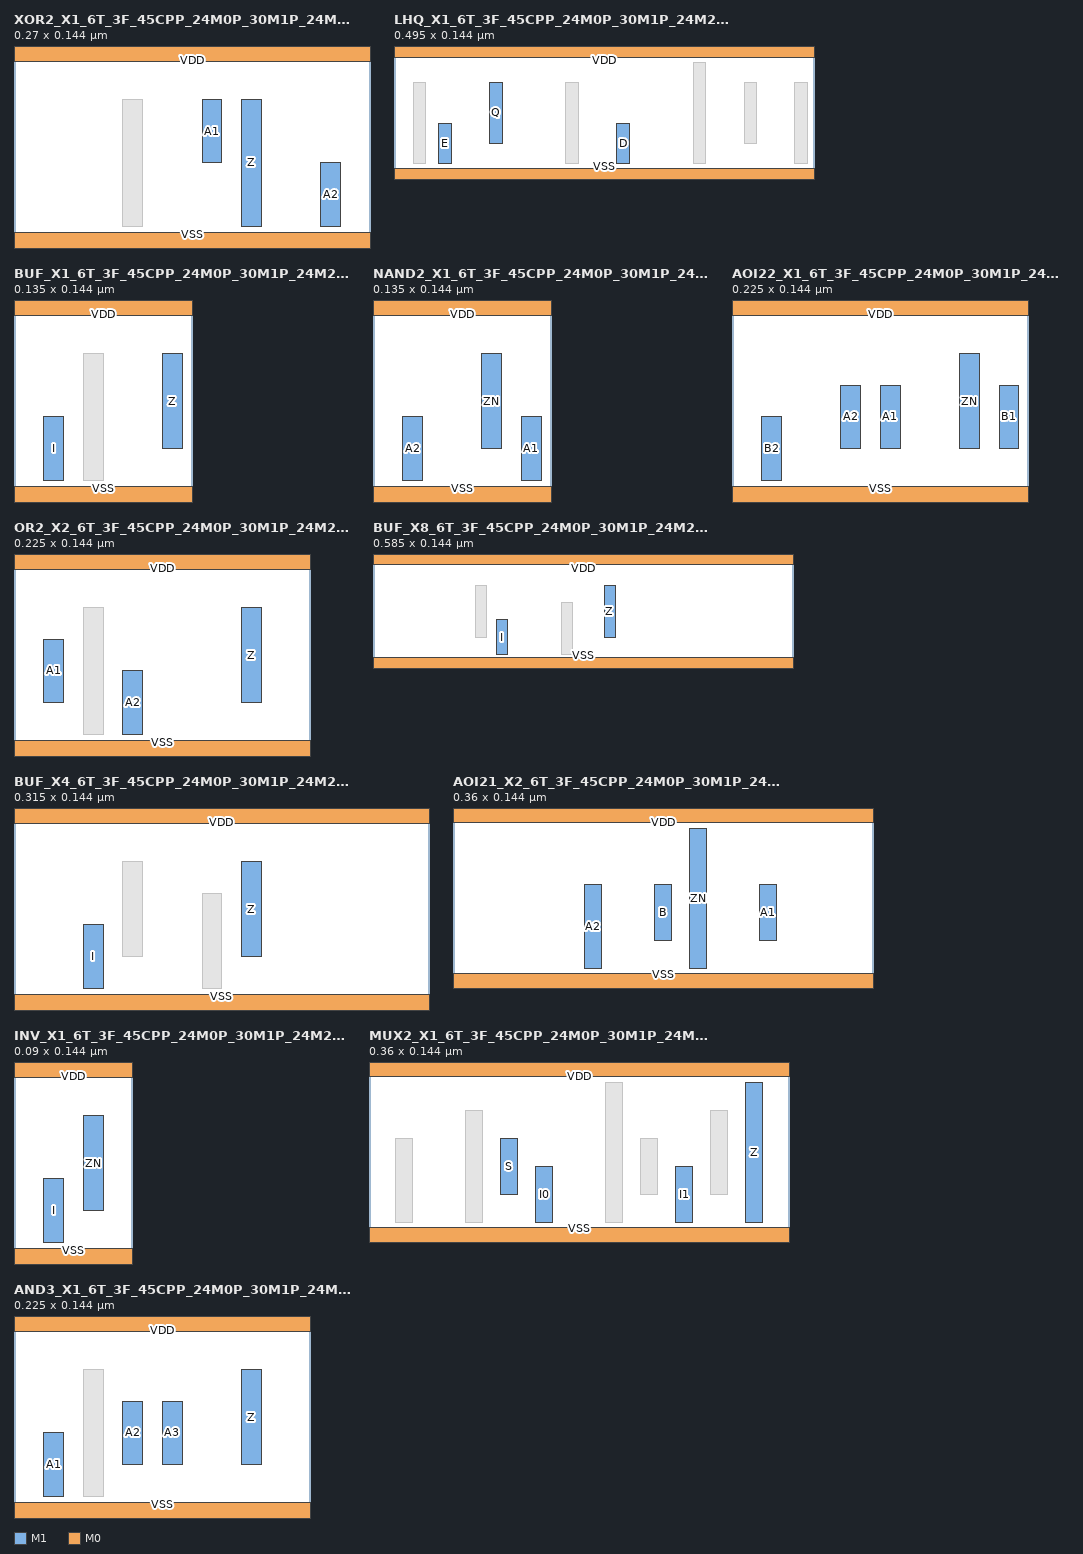
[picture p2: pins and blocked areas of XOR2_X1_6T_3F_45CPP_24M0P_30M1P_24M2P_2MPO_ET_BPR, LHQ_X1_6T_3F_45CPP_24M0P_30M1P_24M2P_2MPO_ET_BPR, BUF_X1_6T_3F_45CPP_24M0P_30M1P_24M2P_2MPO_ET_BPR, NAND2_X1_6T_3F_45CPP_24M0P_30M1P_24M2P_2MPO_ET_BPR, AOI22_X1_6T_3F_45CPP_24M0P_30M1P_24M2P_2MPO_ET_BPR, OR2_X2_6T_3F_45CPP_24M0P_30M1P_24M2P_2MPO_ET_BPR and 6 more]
MACRO XOR2_X1_6T_3F_45CPP_24M0P_30M1P_24M2P_2MPO_ET_BPR
  CLASS CORE ;
  ORIGIN 0 0 ;
  FOREIGN XOR2_X1_6T_3F_45CPP_24M0P_30M1P_24M2P_2MPO_ET_BPR 0 0 ;
  SIZE 0.2700 BY 0.1440 ;
  SYMMETRY X Y ;
  SITE coresite ;
  PIN Z
    DIRECTION OUTPUT ;
    USE SIGNAL ;
    PORT
      LAYER M1 ;
        RECT 0.1725 0.1080 0.1875 0.0120 ;
    END
  END Z
  PIN A1
    DIRECTION INPUT ;
    USE SIGNAL ;
    PORT
      LAYER M1 ;
        RECT 0.1425 0.1080 0.1575 0.0600 ;
    END
  END A1
  PIN A2
    DIRECTION INPUT ;
    USE SIGNAL ;
    PORT
      LAYER M1 ;
        RECT 0.2325 0.0600 0.2475 0.0120 ;
    END
  END A2
  PIN VDD
    DIRECTION INOUT ;
    USE POWER ;
    SHAPE ABUTMENT ;
    PORT
      LAYER M0 ;
        RECT 0.0000 0.1370 0.2700 0.1510 ;
    END
  END VDD
  PIN VSS
    DIRECTION INOUT ;
    USE GROUND ;
    SHAPE ABUTMENT ;
    PORT
      LAYER M0 ;
        RECT 0.0000 -0.0070 0.2700 0.0070 ;
    END
  END VSS
  OBS
      LAYER M1 ;
        RECT 0.0825 0.1080 0.0975 0.0120 ;
  END
END XOR2_X1_6T_3F_45CPP_24M0P_30M1P_24M2P_2MPO_ET_BPR

MACRO LHQ_X1_6T_3F_45CPP_24M0P_30M1P_24M2P_2MPO_ET_BPR
  CLASS CORE ;
  ORIGIN 0 0 ;
  FOREIGN LHQ_X1_6T_3F_45CPP_24M0P_30M1P_24M2P_2MPO_ET_BPR 0 0 ;
  SIZE 0.4950 BY 0.1440 ;
  SYMMETRY X Y ;
  SITE coresite ;
  PIN Q
    DIRECTION OUTPUT ;
    USE SIGNAL ;
    PORT
      LAYER M1 ;
        RECT 0.1125 0.1080 0.1275 0.0360 ;
    END
  END Q
  PIN D
    DIRECTION INPUT ;
    USE SIGNAL ;
    PORT
      LAYER M1 ;
        RECT 0.2625 0.0600 0.2775 0.0120 ;
    END
  END D
  PIN E
    DIRECTION INPUT ;
    USE SIGNAL ;
    PORT
      LAYER M1 ;
        RECT 0.0525 0.0600 0.0675 0.0120 ;
    END
  END E
  PIN VDD
    DIRECTION INOUT ;
    USE POWER ;
    SHAPE ABUTMENT ;
    PORT
      LAYER M0 ;
        RECT 0.0000 0.1370 0.4950 0.1510 ;
    END
  END VDD
  PIN VSS
    DIRECTION INOUT ;
    USE GROUND ;
    SHAPE ABUTMENT ;
    PORT
      LAYER M0 ;
        RECT 0.0000 -0.0070 0.4950 0.0070 ;
    END
  END VSS
  OBS
      LAYER M1 ;
        RECT 0.3525 0.1320 0.3675 0.0120 ;
        RECT 0.2025 0.1080 0.2175 0.0120 ;
        RECT 0.4725 0.1080 0.4875 0.0120 ;
        RECT 0.0225 0.1080 0.0375 0.0120 ;
        RECT 0.4125 0.1080 0.4275 0.0360 ;
  END
END LHQ_X1_6T_3F_45CPP_24M0P_30M1P_24M2P_2MPO_ET_BPR

MACRO BUF_X1_6T_3F_45CPP_24M0P_30M1P_24M2P_2MPO_ET_BPR
  CLASS CORE ;
  ORIGIN 0 0 ;
  FOREIGN BUF_X1_6T_3F_45CPP_24M0P_30M1P_24M2P_2MPO_ET_BPR 0 0 ;
  SIZE 0.1350 BY 0.1440 ;
  SYMMETRY X Y ;
  SITE coresite ;
  PIN Z
    DIRECTION OUTPUT ;
    USE SIGNAL ;
    PORT
      LAYER M1 ;
        RECT 0.1125 0.1080 0.1275 0.0360 ;
    END
  END Z
  PIN I
    DIRECTION INPUT ;
    USE SIGNAL ;
    PORT
      LAYER M1 ;
        RECT 0.0225 0.0600 0.0375 0.0120 ;
    END
  END I
  PIN VDD
    DIRECTION INOUT ;
    USE POWER ;
    SHAPE ABUTMENT ;
    PORT
      LAYER M0 ;
        RECT 0.0000 0.1370 0.1350 0.1510 ;
    END
  END VDD
  PIN VSS
    DIRECTION INOUT ;
    USE GROUND ;
    SHAPE ABUTMENT ;
    PORT
      LAYER M0 ;
        RECT 0.0000 -0.0070 0.1350 0.0070 ;
    END
  END VSS
  OBS
      LAYER M1 ;
        RECT 0.0525 0.1080 0.0675 0.0120 ;
  END
END BUF_X1_6T_3F_45CPP_24M0P_30M1P_24M2P_2MPO_ET_BPR

MACRO NAND2_X1_6T_3F_45CPP_24M0P_30M1P_24M2P_2MPO_ET_BPR
  CLASS CORE ;
  ORIGIN 0 0 ;
  FOREIGN NAND2_X1_6T_3F_45CPP_24M0P_30M1P_24M2P_2MPO_ET_BPR 0 0 ;
  SIZE 0.1350 BY 0.1440 ;
  SYMMETRY X Y ;
  SITE coresite ;
  PIN ZN
    DIRECTION OUTPUT ;
    USE SIGNAL ;
    PORT
      LAYER M1 ;
        RECT 0.0825 0.1080 0.0975 0.0360 ;
    END
  END ZN
  PIN A1
    DIRECTION INPUT ;
    USE SIGNAL ;
    PORT
      LAYER M1 ;
        RECT 0.1125 0.0600 0.1275 0.0120 ;
    END
  END A1
  PIN A2
    DIRECTION INPUT ;
    USE SIGNAL ;
    PORT
      LAYER M1 ;
        RECT 0.0225 0.0600 0.0375 0.0120 ;
    END
  END A2
  PIN VDD
    DIRECTION INOUT ;
    USE POWER ;
    SHAPE ABUTMENT ;
    PORT
      LAYER M0 ;
        RECT 0.0000 0.1370 0.1350 0.1510 ;
    END
  END VDD
  PIN VSS
    DIRECTION INOUT ;
    USE GROUND ;
    SHAPE ABUTMENT ;
    PORT
      LAYER M0 ;
        RECT 0.0000 -0.0070 0.1350 0.0070 ;
    END
  END VSS
END NAND2_X1_6T_3F_45CPP_24M0P_30M1P_24M2P_2MPO_ET_BPR

MACRO AOI22_X1_6T_3F_45CPP_24M0P_30M1P_24M2P_2MPO_ET_BPR
  CLASS CORE ;
  ORIGIN 0 0 ;
  FOREIGN AOI22_X1_6T_3F_45CPP_24M0P_30M1P_24M2P_2MPO_ET_BPR 0 0 ;
  SIZE 0.2250 BY 0.1440 ;
  SYMMETRY X Y ;
  SITE coresite ;
  PIN A2
    DIRECTION INPUT ;
    USE SIGNAL ;
    PORT
      LAYER M1 ;
        RECT 0.0825 0.0840 0.0975 0.0360 ;
    END
  END A2
  PIN A1
    DIRECTION INPUT ;
    USE SIGNAL ;
    PORT
      LAYER M1 ;
        RECT 0.1125 0.0840 0.1275 0.0360 ;
    END
  END A1
  PIN ZN
    DIRECTION OUTPUT ;
    USE SIGNAL ;
    PORT
      LAYER M1 ;
        RECT 0.1725 0.1080 0.1875 0.0360 ;
    END
  END ZN
  PIN B1
    DIRECTION INPUT ;
    USE SIGNAL ;
    PORT
      LAYER M1 ;
        RECT 0.2025 0.0840 0.2175 0.0360 ;
    END
  END B1
  PIN B2
    DIRECTION INPUT ;
    USE SIGNAL ;
    PORT
      LAYER M1 ;
        RECT 0.0225 0.0600 0.0375 0.0120 ;
    END
  END B2
  PIN VDD
    DIRECTION INOUT ;
    USE POWER ;
    SHAPE ABUTMENT ;
    PORT
      LAYER M0 ;
        RECT 0.0000 0.1370 0.2250 0.1510 ;
    END
  END VDD
  PIN VSS
    DIRECTION INOUT ;
    USE GROUND ;
    SHAPE ABUTMENT ;
    PORT
      LAYER M0 ;
        RECT 0.0000 -0.0070 0.2250 0.0070 ;
    END
  END VSS
END AOI22_X1_6T_3F_45CPP_24M0P_30M1P_24M2P_2MPO_ET_BPR

MACRO OR2_X2_6T_3F_45CPP_24M0P_30M1P_24M2P_2MPO_ET_BPR
  CLASS CORE ;
  ORIGIN 0 0 ;
  FOREIGN OR2_X2_6T_3F_45CPP_24M0P_30M1P_24M2P_2MPO_ET_BPR 0 0 ;
  SIZE 0.2250 BY 0.1440 ;
  SYMMETRY X Y ;
  SITE coresite ;
  PIN Z
    DIRECTION OUTPUT ;
    USE SIGNAL ;
    PORT
      LAYER M1 ;
        RECT 0.1725 0.1080 0.1875 0.0360 ;
    END
  END Z
  PIN A1
    DIRECTION INPUT ;
    USE SIGNAL ;
    PORT
      LAYER M1 ;
        RECT 0.0225 0.0840 0.0375 0.0360 ;
    END
  END A1
  PIN A2
    DIRECTION INPUT ;
    USE SIGNAL ;
    PORT
      LAYER M1 ;
        RECT 0.0825 0.0600 0.0975 0.0120 ;
    END
  END A2
  PIN VDD
    DIRECTION INOUT ;
    USE POWER ;
    SHAPE ABUTMENT ;
    PORT
      LAYER M0 ;
        RECT 0.0000 0.1370 0.2250 0.1510 ;
    END
  END VDD
  PIN VSS
    DIRECTION INOUT ;
    USE GROUND ;
    SHAPE ABUTMENT ;
    PORT
      LAYER M0 ;
        RECT 0.0000 -0.0070 0.2250 0.0070 ;
    END
  END VSS
  OBS
      LAYER M1 ;
        RECT 0.0525 0.1080 0.0675 0.0120 ;
  END
END OR2_X2_6T_3F_45CPP_24M0P_30M1P_24M2P_2MPO_ET_BPR

MACRO BUF_X8_6T_3F_45CPP_24M0P_30M1P_24M2P_2MPO_ET_BPR
  CLASS CORE ;
  ORIGIN 0 0 ;
  FOREIGN BUF_X8_6T_3F_45CPP_24M0P_30M1P_24M2P_2MPO_ET_BPR 0 0 ;
  SIZE 0.5850 BY 0.1440 ;
  SYMMETRY X Y ;
  SITE coresite ;
  PIN Z
    DIRECTION OUTPUT ;
    USE SIGNAL ;
    PORT
      LAYER M1 ;
        RECT 0.3225 0.1080 0.3375 0.0360 ;
    END
  END Z
  PIN I
    DIRECTION INPUT ;
    USE SIGNAL ;
    PORT
      LAYER M1 ;
        RECT 0.1725 0.0600 0.1875 0.0120 ;
    END
  END I
  PIN VDD
    DIRECTION INOUT ;
    USE POWER ;
    SHAPE ABUTMENT ;
    PORT
      LAYER M0 ;
        RECT 0.0000 0.1370 0.5850 0.1510 ;
    END
  END VDD
  PIN VSS
    DIRECTION INOUT ;
    USE GROUND ;
    SHAPE ABUTMENT ;
    PORT
      LAYER M0 ;
        RECT 0.0000 -0.0070 0.5850 0.0070 ;
    END
  END VSS
  OBS
      LAYER M1 ;
        RECT 0.2625 0.0840 0.2775 0.0120 ;
        RECT 0.1425 0.1080 0.1575 0.0360 ;
  END
END BUF_X8_6T_3F_45CPP_24M0P_30M1P_24M2P_2MPO_ET_BPR

MACRO BUF_X4_6T_3F_45CPP_24M0P_30M1P_24M2P_2MPO_ET_BPR
  CLASS CORE ;
  ORIGIN 0 0 ;
  FOREIGN BUF_X4_6T_3F_45CPP_24M0P_30M1P_24M2P_2MPO_ET_BPR 0 0 ;
  SIZE 0.3150 BY 0.1440 ;
  SYMMETRY X Y ;
  SITE coresite ;
  PIN Z
    DIRECTION OUTPUT ;
    USE SIGNAL ;
    PORT
      LAYER M1 ;
        RECT 0.1725 0.1080 0.1875 0.0360 ;
    END
  END Z
  PIN I
    DIRECTION INPUT ;
    USE SIGNAL ;
    PORT
      LAYER M1 ;
        RECT 0.0525 0.0600 0.0675 0.0120 ;
    END
  END I
  PIN VDD
    DIRECTION INOUT ;
    USE POWER ;
    SHAPE ABUTMENT ;
    PORT
      LAYER M0 ;
        RECT 0.0000 0.1370 0.3150 0.1510 ;
    END
  END VDD
  PIN VSS
    DIRECTION INOUT ;
    USE GROUND ;
    SHAPE ABUTMENT ;
    PORT
      LAYER M0 ;
        RECT 0.0000 -0.0070 0.3150 0.0070 ;
    END
  END VSS
  OBS
      LAYER M1 ;
        RECT 0.0825 0.1080 0.0975 0.0360 ;
        RECT 0.1425 0.0840 0.1575 0.0120 ;
  END
END BUF_X4_6T_3F_45CPP_24M0P_30M1P_24M2P_2MPO_ET_BPR

MACRO AOI21_X2_6T_3F_45CPP_24M0P_30M1P_24M2P_2MPO_ET_BPR
  CLASS CORE ;
  ORIGIN 0 0 ;
  FOREIGN AOI21_X2_6T_3F_45CPP_24M0P_30M1P_24M2P_2MPO_ET_BPR 0 0 ;
  SIZE 0.3600 BY 0.1440 ;
  SYMMETRY X Y ;
  SITE coresite ;
  PIN A1
    DIRECTION INPUT ;
    USE SIGNAL ;
    PORT
      LAYER M1 ;
        RECT 0.2625 0.0840 0.2775 0.0360 ;
    END
  END A1
  PIN A2
    DIRECTION INPUT ;
    USE SIGNAL ;
    PORT
      LAYER M1 ;
        RECT 0.1125 0.0840 0.1275 0.0120 ;
    END
  END A2
  PIN ZN
    DIRECTION OUTPUT ;
    USE SIGNAL ;
    PORT
      LAYER M1 ;
        RECT 0.2025 0.1320 0.2175 0.0120 ;
    END
  END ZN
  PIN B
    DIRECTION INPUT ;
    USE SIGNAL ;
    PORT
      LAYER M1 ;
        RECT 0.1725 0.0840 0.1875 0.0360 ;
    END
  END B
  PIN VDD
    DIRECTION INOUT ;
    USE POWER ;
    SHAPE ABUTMENT ;
    PORT
      LAYER M0 ;
        RECT 0.0000 0.1370 0.3600 0.1510 ;
    END
  END VDD
  PIN VSS
    DIRECTION INOUT ;
    USE GROUND ;
    SHAPE ABUTMENT ;
    PORT
      LAYER M0 ;
        RECT 0.0000 -0.0070 0.3600 0.0070 ;
    END
  END VSS
END AOI21_X2_6T_3F_45CPP_24M0P_30M1P_24M2P_2MPO_ET_BPR

MACRO INV_X1_6T_3F_45CPP_24M0P_30M1P_24M2P_2MPO_ET_BPR
  CLASS CORE ;
  ORIGIN 0 0 ;
  FOREIGN INV_X1_6T_3F_45CPP_24M0P_30M1P_24M2P_2MPO_ET_BPR 0 0 ;
  SIZE 0.0900 BY 0.1440 ;
  SYMMETRY X Y ;
  SITE coresite ;
  PIN ZN
    DIRECTION OUTPUT ;
    USE SIGNAL ;
    PORT
      LAYER M1 ;
        RECT 0.0525 0.1080 0.0675 0.0360 ;
    END
  END ZN
  PIN I
    DIRECTION INPUT ;
    USE SIGNAL ;
    PORT
      LAYER M1 ;
        RECT 0.0225 0.0600 0.0375 0.0120 ;
    END
  END I
  PIN VDD
    DIRECTION INOUT ;
    USE POWER ;
    SHAPE ABUTMENT ;
    PORT
      LAYER M0 ;
        RECT 0.0000 0.1370 0.0900 0.1510 ;
    END
  END VDD
  PIN VSS
    DIRECTION INOUT ;
    USE GROUND ;
    SHAPE ABUTMENT ;
    PORT
      LAYER M0 ;
        RECT 0.0000 -0.0070 0.0900 0.0070 ;
    END
  END VSS
END INV_X1_6T_3F_45CPP_24M0P_30M1P_24M2P_2MPO_ET_BPR

MACRO MUX2_X1_6T_3F_45CPP_24M0P_30M1P_24M2P_2MPO_ET_BPR
  CLASS CORE ;
  ORIGIN 0 0 ;
  FOREIGN MUX2_X1_6T_3F_45CPP_24M0P_30M1P_24M2P_2MPO_ET_BPR 0 0 ;
  SIZE 0.3600 BY 0.1440 ;
  SYMMETRY X Y ;
  SITE coresite ;
  PIN Z
    DIRECTION OUTPUT ;
    USE SIGNAL ;
    PORT
      LAYER M1 ;
        RECT 0.3225 0.1320 0.3375 0.0120 ;
    END
  END Z
  PIN I0
    DIRECTION INPUT ;
    USE SIGNAL ;
    PORT
      LAYER M1 ;
        RECT 0.1425 0.0600 0.1575 0.0120 ;
    END
  END I0
  PIN I1
    DIRECTION INPUT ;
    USE SIGNAL ;
    PORT
      LAYER M1 ;
        RECT 0.2625 0.0600 0.2775 0.0120 ;
    END
  END I1
  PIN S
    DIRECTION INPUT ;
    USE SIGNAL ;
    PORT
      LAYER M1 ;
        RECT 0.1125 0.0840 0.1275 0.0360 ;
    END
  END S
  PIN VDD
    DIRECTION INOUT ;
    USE POWER ;
    SHAPE ABUTMENT ;
    PORT
      LAYER M0 ;
        RECT 0.0000 0.1370 0.3600 0.1510 ;
    END
  END VDD
  PIN VSS
    DIRECTION INOUT ;
    USE GROUND ;
    SHAPE ABUTMENT ;
    PORT
      LAYER M0 ;
        RECT 0.0000 -0.0070 0.3600 0.0070 ;
    END
  END VSS
  OBS
      LAYER M1 ;
        RECT 0.0825 0.1080 0.0975 0.0120 ;
        RECT 0.2925 0.1080 0.3075 0.0360 ;
        RECT 0.2025 0.1320 0.2175 0.0120 ;
        RECT 0.2325 0.0840 0.2475 0.0360 ;
        RECT 0.0225 0.0840 0.0375 0.0120 ;
  END
END MUX2_X1_6T_3F_45CPP_24M0P_30M1P_24M2P_2MPO_ET_BPR

MACRO AND3_X1_6T_3F_45CPP_24M0P_30M1P_24M2P_2MPO_ET_BPR
  CLASS CORE ;
  ORIGIN 0 0 ;
  FOREIGN AND3_X1_6T_3F_45CPP_24M0P_30M1P_24M2P_2MPO_ET_BPR 0 0 ;
  SIZE 0.2250 BY 0.1440 ;
  SYMMETRY X Y ;
  SITE coresite ;
  PIN Z
    DIRECTION OUTPUT ;
    USE SIGNAL ;
    PORT
      LAYER M1 ;
        RECT 0.1725 0.1080 0.1875 0.0360 ;
    END
  END Z
  PIN A1
    DIRECTION INPUT ;
    USE SIGNAL ;
    PORT
      LAYER M1 ;
        RECT 0.0225 0.0600 0.0375 0.0120 ;
    END
  END A1
  PIN A2
    DIRECTION INPUT ;
    USE SIGNAL ;
    PORT
      LAYER M1 ;
        RECT 0.0825 0.0840 0.0975 0.0360 ;
    END
  END A2
  PIN A3
    DIRECTION INPUT ;
    USE SIGNAL ;
    PORT
      LAYER M1 ;
        RECT 0.1125 0.0840 0.1275 0.0360 ;
    END
  END A3
  PIN VDD
    DIRECTION INOUT ;
    USE POWER ;
    SHAPE ABUTMENT ;
    PORT
      LAYER M0 ;
        RECT 0.0000 0.1370 0.2250 0.1510 ;
    END
  END VDD
  PIN VSS
    DIRECTION INOUT ;
    USE GROUND ;
    SHAPE ABUTMENT ;
    PORT
      LAYER M0 ;
        RECT 0.0000 -0.0070 0.2250 0.0070 ;
    END
  END VSS
  OBS
      LAYER M1 ;
        RECT 0.0525 0.1080 0.0675 0.0120 ;
  END
END AND3_X1_6T_3F_45CPP_24M0P_30M1P_24M2P_2MPO_ET_BPR

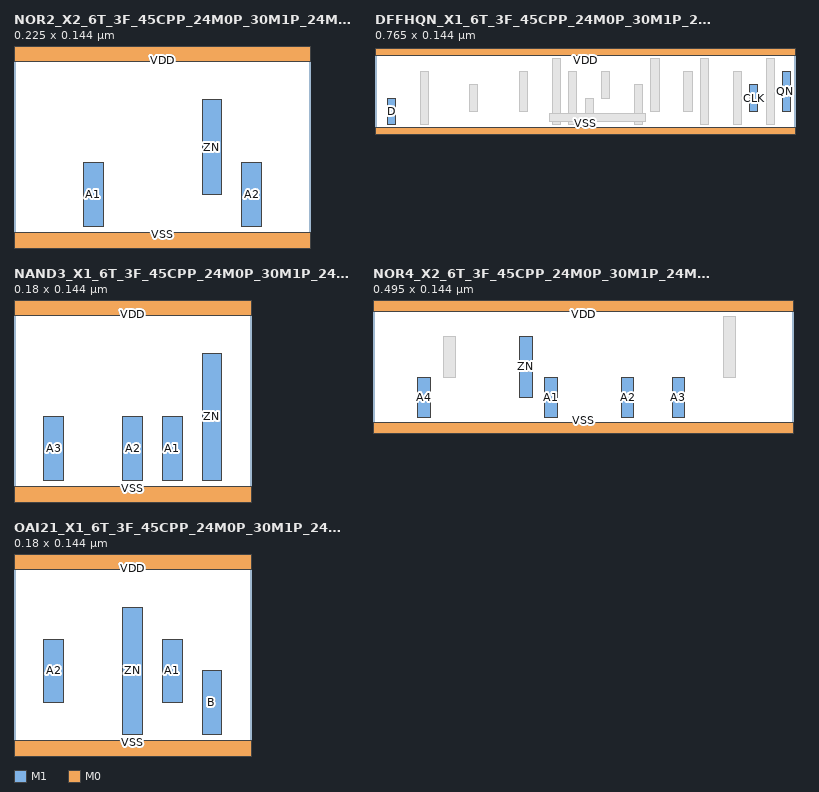
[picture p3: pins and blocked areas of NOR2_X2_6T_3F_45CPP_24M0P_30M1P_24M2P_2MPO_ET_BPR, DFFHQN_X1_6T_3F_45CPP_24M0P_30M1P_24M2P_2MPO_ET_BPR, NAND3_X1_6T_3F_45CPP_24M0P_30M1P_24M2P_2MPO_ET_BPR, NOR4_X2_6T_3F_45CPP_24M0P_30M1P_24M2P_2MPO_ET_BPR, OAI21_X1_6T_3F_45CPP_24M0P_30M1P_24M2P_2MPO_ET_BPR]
MACRO NOR2_X2_6T_3F_45CPP_24M0P_30M1P_24M2P_2MPO_ET_BPR
  CLASS CORE ;
  ORIGIN 0 0 ;
  FOREIGN NOR2_X2_6T_3F_45CPP_24M0P_30M1P_24M2P_2MPO_ET_BPR 0 0 ;
  SIZE 0.2250 BY 0.1440 ;
  SYMMETRY X Y ;
  SITE coresite ;
  PIN A2
    DIRECTION INPUT ;
    USE SIGNAL ;
    PORT
      LAYER M1 ;
        RECT 0.1725 0.0600 0.1875 0.0120 ;
    END
  END A2
  PIN A1
    DIRECTION INPUT ;
    USE SIGNAL ;
    PORT
      LAYER M1 ;
        RECT 0.0525 0.0600 0.0675 0.0120 ;
    END
  END A1
  PIN ZN
    DIRECTION OUTPUT ;
    USE SIGNAL ;
    PORT
      LAYER M1 ;
        RECT 0.1425 0.1080 0.1575 0.0360 ;
    END
  END ZN
  PIN VDD
    DIRECTION INOUT ;
    USE POWER ;
    SHAPE ABUTMENT ;
    PORT
      LAYER M0 ;
        RECT 0.0000 0.1370 0.2250 0.1510 ;
    END
  END VDD
  PIN VSS
    DIRECTION INOUT ;
    USE GROUND ;
    SHAPE ABUTMENT ;
    PORT
      LAYER M0 ;
        RECT 0.0000 -0.0070 0.2250 0.0070 ;
    END
  END VSS
END NOR2_X2_6T_3F_45CPP_24M0P_30M1P_24M2P_2MPO_ET_BPR

MACRO DFFHQN_X1_6T_3F_45CPP_24M0P_30M1P_24M2P_2MPO_ET_BPR
  CLASS CORE ;
  ORIGIN 0 0 ;
  FOREIGN DFFHQN_X1_6T_3F_45CPP_24M0P_30M1P_24M2P_2MPO_ET_BPR 0 0 ;
  SIZE 0.7650 BY 0.1440 ;
  SYMMETRY X Y ;
  SITE coresite ;
  PIN D
    DIRECTION INPUT ;
    USE SIGNAL ;
    PORT
      LAYER M1 ;
        RECT 0.0225 0.0600 0.0375 0.0120 ;
    END
  END D
  PIN CLK
    DIRECTION INPUT ;
    USE SIGNAL ;
    PORT
      LAYER M1 ;
        RECT 0.6825 0.0840 0.6975 0.0360 ;
    END
  END CLK
  PIN QN
    DIRECTION OUTPUT ;
    USE SIGNAL ;
    PORT
      LAYER M1 ;
        RECT 0.7425 0.1080 0.7575 0.0360 ;
    END
  END QN
  PIN VDD
    DIRECTION INOUT ;
    USE POWER ;
    SHAPE ABUTMENT ;
    PORT
      LAYER M0 ;
        RECT 0.0000 0.1370 0.7650 0.1510 ;
    END
  END VDD
  PIN VSS
    DIRECTION INOUT ;
    USE GROUND ;
    SHAPE ABUTMENT ;
    PORT
      LAYER M0 ;
        RECT 0.0000 -0.0070 0.7650 0.0070 ;
    END
  END VSS
  OBS
      LAYER V1 ;
        RECT 0.4730 0.0170 0.4870 0.0310 ;
        RECT 0.3830 0.0170 0.3970 0.0310 ;
        RECT 0.3230 0.0170 0.3370 0.0310 ;
      LAYER M1 ;
        RECT 0.0825 0.1080 0.0975 0.0120 ;
        RECT 0.3525 0.1080 0.3675 0.0120 ;
        RECT 0.7125 0.1320 0.7275 0.0120 ;
        RECT 0.2625 0.1080 0.2775 0.0360 ;
        RECT 0.4725 0.0840 0.4875 0.0120 ;
        RECT 0.5925 0.1320 0.6075 0.0120 ;
        RECT 0.3825 0.0600 0.3975 0.0120 ;
        RECT 0.5025 0.1320 0.5175 0.0360 ;
        RECT 0.3225 0.1320 0.3375 0.0120 ;
        RECT 0.6525 0.1080 0.6675 0.0120 ;
        RECT 0.5625 0.1080 0.5775 0.0360 ;
        RECT 0.4125 0.1080 0.4275 0.0600 ;
        RECT 0.1725 0.0840 0.1875 0.0360 ;
      LAYER M2 ;
        RECT 0.3180 0.0170 0.4920 0.0310 ;
  END
END DFFHQN_X1_6T_3F_45CPP_24M0P_30M1P_24M2P_2MPO_ET_BPR

MACRO NAND3_X1_6T_3F_45CPP_24M0P_30M1P_24M2P_2MPO_ET_BPR
  CLASS CORE ;
  ORIGIN 0 0 ;
  FOREIGN NAND3_X1_6T_3F_45CPP_24M0P_30M1P_24M2P_2MPO_ET_BPR 0 0 ;
  SIZE 0.1800 BY 0.1440 ;
  SYMMETRY X Y ;
  SITE coresite ;
  PIN ZN
    DIRECTION OUTPUT ;
    USE SIGNAL ;
    PORT
      LAYER M1 ;
        RECT 0.1425 0.1080 0.1575 0.0120 ;
    END
  END ZN
  PIN A1
    DIRECTION INPUT ;
    USE SIGNAL ;
    PORT
      LAYER M1 ;
        RECT 0.1125 0.0600 0.1275 0.0120 ;
    END
  END A1
  PIN A2
    DIRECTION INPUT ;
    USE SIGNAL ;
    PORT
      LAYER M1 ;
        RECT 0.0825 0.0600 0.0975 0.0120 ;
    END
  END A2
  PIN A3
    DIRECTION INPUT ;
    USE SIGNAL ;
    PORT
      LAYER M1 ;
        RECT 0.0225 0.0600 0.0375 0.0120 ;
    END
  END A3
  PIN VDD
    DIRECTION INOUT ;
    USE POWER ;
    SHAPE ABUTMENT ;
    PORT
      LAYER M0 ;
        RECT 0.0000 0.1370 0.1800 0.1510 ;
    END
  END VDD
  PIN VSS
    DIRECTION INOUT ;
    USE GROUND ;
    SHAPE ABUTMENT ;
    PORT
      LAYER M0 ;
        RECT 0.0000 -0.0070 0.1800 0.0070 ;
    END
  END VSS
END NAND3_X1_6T_3F_45CPP_24M0P_30M1P_24M2P_2MPO_ET_BPR

MACRO NOR4_X2_6T_3F_45CPP_24M0P_30M1P_24M2P_2MPO_ET_BPR
  CLASS CORE ;
  ORIGIN 0 0 ;
  FOREIGN NOR4_X2_6T_3F_45CPP_24M0P_30M1P_24M2P_2MPO_ET_BPR 0 0 ;
  SIZE 0.4950 BY 0.1440 ;
  SYMMETRY X Y ;
  SITE coresite ;
  PIN A4
    DIRECTION INPUT ;
    USE SIGNAL ;
    PORT
      LAYER M1 ;
        RECT 0.0525 0.0600 0.0675 0.0120 ;
    END
  END A4
  PIN A3
    DIRECTION INPUT ;
    USE SIGNAL ;
    PORT
      LAYER M1 ;
        RECT 0.3525 0.0600 0.3675 0.0120 ;
    END
  END A3
  PIN A2
    DIRECTION INPUT ;
    USE SIGNAL ;
    PORT
      LAYER M1 ;
        RECT 0.2925 0.0600 0.3075 0.0120 ;
    END
  END A2
  PIN A1
    DIRECTION INPUT ;
    USE SIGNAL ;
    PORT
      LAYER M1 ;
        RECT 0.2025 0.0600 0.2175 0.0120 ;
    END
  END A1
  PIN ZN
    DIRECTION OUTPUT ;
    USE SIGNAL ;
    PORT
      LAYER M1 ;
        RECT 0.1725 0.1080 0.1875 0.0360 ;
    END
  END ZN
  PIN VDD
    DIRECTION INOUT ;
    USE POWER ;
    SHAPE ABUTMENT ;
    PORT
      LAYER M0 ;
        RECT 0.0000 0.1370 0.4950 0.1510 ;
    END
  END VDD
  PIN VSS
    DIRECTION INOUT ;
    USE GROUND ;
    SHAPE ABUTMENT ;
    PORT
      LAYER M0 ;
        RECT 0.0000 -0.0070 0.4950 0.0070 ;
    END
  END VSS
  OBS
      LAYER M1 ;
        RECT 0.0825 0.1080 0.0975 0.0600 ;
        RECT 0.4125 0.1320 0.4275 0.0600 ;
  END
END NOR4_X2_6T_3F_45CPP_24M0P_30M1P_24M2P_2MPO_ET_BPR

MACRO OAI21_X1_6T_3F_45CPP_24M0P_30M1P_24M2P_2MPO_ET_BPR
  CLASS CORE ;
  ORIGIN 0 0 ;
  FOREIGN OAI21_X1_6T_3F_45CPP_24M0P_30M1P_24M2P_2MPO_ET_BPR 0 0 ;
  SIZE 0.1800 BY 0.1440 ;
  SYMMETRY X Y ;
  SITE coresite ;
  PIN B
    DIRECTION INPUT ;
    USE SIGNAL ;
    PORT
      LAYER M1 ;
        RECT 0.1425 0.0600 0.1575 0.0120 ;
    END
  END B
  PIN A1
    DIRECTION INPUT ;
    USE SIGNAL ;
    PORT
      LAYER M1 ;
        RECT 0.1125 0.0840 0.1275 0.0360 ;
    END
  END A1
  PIN ZN
    DIRECTION OUTPUT ;
    USE SIGNAL ;
    PORT
      LAYER M1 ;
        RECT 0.0825 0.1080 0.0975 0.0120 ;
    END
  END ZN
  PIN A2
    DIRECTION INPUT ;
    USE SIGNAL ;
    PORT
      LAYER M1 ;
        RECT 0.0225 0.0840 0.0375 0.0360 ;
    END
  END A2
  PIN VDD
    DIRECTION INOUT ;
    USE POWER ;
    SHAPE ABUTMENT ;
    PORT
      LAYER M0 ;
        RECT 0.0000 0.1370 0.1800 0.1510 ;
    END
  END VDD
  PIN VSS
    DIRECTION INOUT ;
    USE GROUND ;
    SHAPE ABUTMENT ;
    PORT
      LAYER M0 ;
        RECT 0.0000 -0.0070 0.1800 0.0070 ;
    END
  END VSS
END OAI21_X1_6T_3F_45CPP_24M0P_30M1P_24M2P_2MPO_ET_BPR

END LIBRARY
